VERSION 5.8 ;
BUSBITCHARS "[]" ;
DIVIDERCHAR "/" ;

UNITS
  DATABASE MICRONS 1000 ;
END UNITS

MANUFACTURINGGRID 0.001 ;

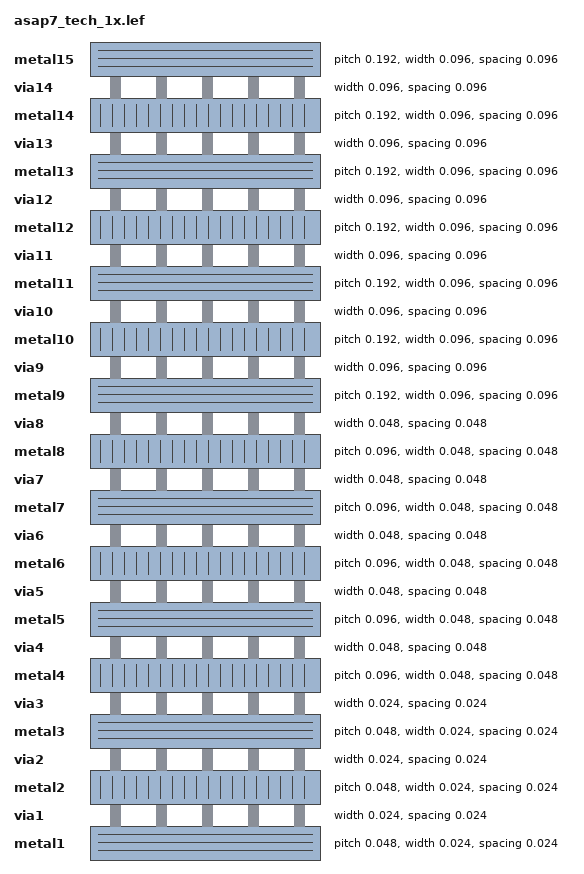
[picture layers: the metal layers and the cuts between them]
LAYER metal1
  TYPE ROUTING ;
  DIRECTION HORIZONTAL ;
  PITCH 0.048 ;
  WIDTH 0.024 ;
  SPACING 0.024 ;
  RESISTANCE RPERSQ 0.35 ;
  CAPACITANCE CPERSQDIST 0.00018 ;
END metal1

LAYER via1
  TYPE CUT ;
  SPACING 0.024 ;
  WIDTH 0.024 ;
  RESISTANCE 4.5 ;
END via1

LAYER metal2
  TYPE ROUTING ;
  DIRECTION VERTICAL ;
  PITCH 0.048 ;
  WIDTH 0.024 ;
  SPACING 0.024 ;
  RESISTANCE RPERSQ 0.35 ;
  CAPACITANCE CPERSQDIST 0.00018 ;
END metal2

LAYER via2
  TYPE CUT ;
  SPACING 0.024 ;
  WIDTH 0.024 ;
  RESISTANCE 4.5 ;
END via2

LAYER metal3
  TYPE ROUTING ;
  DIRECTION HORIZONTAL ;
  PITCH 0.048 ;
  WIDTH 0.024 ;
  SPACING 0.024 ;
  RESISTANCE RPERSQ 0.32 ;
  CAPACITANCE CPERSQDIST 0.00017 ;
END metal3

LAYER via3
  TYPE CUT ;
  SPACING 0.024 ;
  WIDTH 0.024 ;
  RESISTANCE 4.2 ;
END via3

LAYER metal4
  TYPE ROUTING ;
  DIRECTION VERTICAL ;
  PITCH 0.096 ;
  WIDTH 0.048 ;
  SPACING 0.048 ;
  RESISTANCE RPERSQ 0.18 ;
  CAPACITANCE CPERSQDIST 0.00015 ;
END metal4

LAYER via4
  TYPE CUT ;
  SPACING 0.048 ;
  WIDTH 0.048 ;
  RESISTANCE 2.5 ;
END via4

LAYER metal5
  TYPE ROUTING ;
  DIRECTION HORIZONTAL ;
  PITCH 0.096 ;
  WIDTH 0.048 ;
  SPACING 0.048 ;
  RESISTANCE RPERSQ 0.18 ;
  CAPACITANCE CPERSQDIST 0.00015 ;
END metal5

LAYER via5
  TYPE CUT ;
  SPACING 0.048 ;
  WIDTH 0.048 ;
  RESISTANCE 2.5 ;
END via5

LAYER metal6
  TYPE ROUTING ;
  DIRECTION VERTICAL ;
  PITCH 0.096 ;
  WIDTH 0.048 ;
  SPACING 0.048 ;
  RESISTANCE RPERSQ 0.16 ;
  CAPACITANCE CPERSQDIST 0.00014 ;
END metal6

LAYER via6
  TYPE CUT ;
  SPACING 0.048 ;
  WIDTH 0.048 ;
  RESISTANCE 2.2 ;
END via6

LAYER metal7
  TYPE ROUTING ;
  DIRECTION HORIZONTAL ;
  PITCH 0.096 ;
  WIDTH 0.048 ;
  SPACING 0.048 ;
  RESISTANCE RPERSQ 0.16 ;
  CAPACITANCE CPERSQDIST 0.00014 ;
END metal7

LAYER via7
  TYPE CUT ;
  SPACING 0.048 ;
  WIDTH 0.048 ;
  RESISTANCE 2.2 ;
END via7

LAYER metal8
  TYPE ROUTING ;
  DIRECTION VERTICAL ;
  PITCH 0.096 ;
  WIDTH 0.048 ;
  SPACING 0.048 ;
  RESISTANCE RPERSQ 0.14 ;
  CAPACITANCE CPERSQDIST 0.00013 ;
END metal8

LAYER via8
  TYPE CUT ;
  SPACING 0.048 ;
  WIDTH 0.048 ;
  RESISTANCE 1.8 ;
END via8

LAYER metal9
  TYPE ROUTING ;
  DIRECTION HORIZONTAL ;
  PITCH 0.192 ;
  WIDTH 0.096 ;
  SPACING 0.096 ;
  RESISTANCE RPERSQ 0.08 ;
  CAPACITANCE CPERSQDIST 0.00011 ;
END metal9

LAYER via9
  TYPE CUT ;
  SPACING 0.096 ;
  WIDTH 0.096 ;
  RESISTANCE 1.2 ;
END via9

LAYER metal10
  TYPE ROUTING ;
  DIRECTION VERTICAL ;
  PITCH 0.192 ;
  WIDTH 0.096 ;
  SPACING 0.096 ;
  RESISTANCE RPERSQ 0.08 ;
  CAPACITANCE CPERSQDIST 0.00011 ;
END metal10

LAYER via10
  TYPE CUT ;
  SPACING 0.096 ;
  WIDTH 0.096 ;
  RESISTANCE 1.2 ;
END via10

LAYER metal11
  TYPE ROUTING ;
  DIRECTION HORIZONTAL ;
  PITCH 0.192 ;
  WIDTH 0.096 ;
  SPACING 0.096 ;
  RESISTANCE RPERSQ 0.06 ;
  CAPACITANCE CPERSQDIST 0.00010 ;
END metal11

LAYER via11
  TYPE CUT ;
  SPACING 0.096 ;
  WIDTH 0.096 ;
  RESISTANCE 1.0 ;
END via11

LAYER metal12
  TYPE ROUTING ;
  DIRECTION VERTICAL ;
  PITCH 0.192 ;
  WIDTH 0.096 ;
  SPACING 0.096 ;
  RESISTANCE RPERSQ 0.06 ;
  CAPACITANCE CPERSQDIST 0.00010 ;
END metal12

LAYER via12
  TYPE CUT ;
  SPACING 0.096 ;
  WIDTH 0.096 ;
  RESISTANCE 1.0 ;
END via12

LAYER metal13
  TYPE ROUTING ;
  DIRECTION HORIZONTAL ;
  PITCH 0.192 ;
  WIDTH 0.096 ;
  SPACING 0.096 ;
  RESISTANCE RPERSQ 0.04 ;
  CAPACITANCE CPERSQDIST 0.00009 ;
END metal13

LAYER via13
  TYPE CUT ;
  SPACING 0.096 ;
  WIDTH 0.096 ;
  RESISTANCE 0.8 ;
END via13

LAYER metal14
  TYPE ROUTING ;
  DIRECTION VERTICAL ;
  PITCH 0.192 ;
  WIDTH 0.096 ;
  SPACING 0.096 ;
  RESISTANCE RPERSQ 0.04 ;
  CAPACITANCE CPERSQDIST 0.00009 ;
END metal14

LAYER via14
  TYPE CUT ;
  SPACING 0.096 ;
  WIDTH 0.096 ;
  RESISTANCE 0.8 ;
END via14

LAYER metal15
  TYPE ROUTING ;
  DIRECTION HORIZONTAL ;
  PITCH 0.192 ;
  WIDTH 0.096 ;
  SPACING 0.096 ;
  RESISTANCE RPERSQ 0.02 ;
  CAPACITANCE CPERSQDIST 0.00008 ;
END metal15

END LIBRARY
